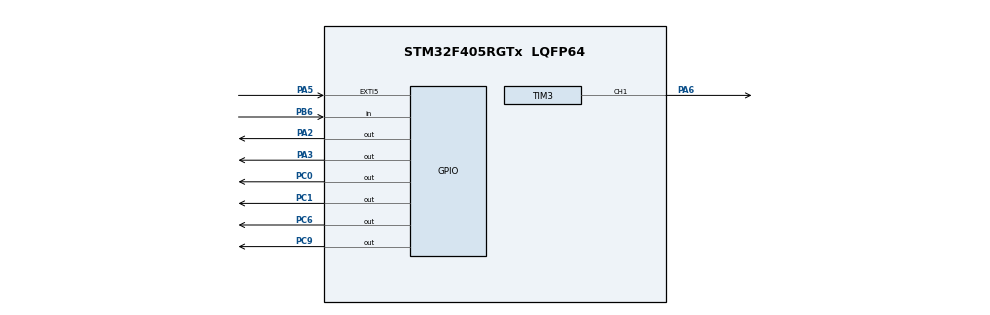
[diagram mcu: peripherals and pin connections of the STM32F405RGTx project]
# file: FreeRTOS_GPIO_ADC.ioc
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Mcu.Family=STM32F4
Mcu.Name=STM32F405RGTx
Mcu.Package=LQFP64
NVIC.PriorityGroup=NVIC_PRIORITYGROUP_4
NVIC.TIM6_DAC_IRQn=true\:15\:0\:false\:false\:true\:false\:true\:true
NVIC.TimeBase=TIM6_DAC_IRQn
NVIC.TimeBaseIP=TIM6
PA2.Signal=GPIO_Output
PA3.Signal=GPIO_Output
PA5.Signal=GPXTI5
PA6.Signal=S_TIM3_CH1
PB6.Signal=GPIO_Input
PC0.Signal=GPIO_Output
PC1.Signal=GPIO_Output
PC6.Signal=GPIO_Output
PC9.Signal=GPIO_Output
ProjectManager.HeapSize=0x200
ProjectManager.StackSize=0x400
ProjectManager.TargetToolchain=STM32CubeIDE
RCC.AHBFreq_Value=16000000
RCC.APB1Freq_Value=16000000
RCC.APB2Freq_Value=16000000
RCC.CortexFreq_Value=16000000
RCC.HSE_VALUE=25000000
RCC.HSI_VALUE=16000000
RCC.LSE_VALUE=32768
RCC.SYSCLKFreq_VALUE=16000000
RCC.VCOOutputFreq_Value=192000000
SH.S_TIM3_CH1.0=TIM3_CH1,PWM Generation1 CH1
TIM2.Period=65535
TIM2.Prescaler=15
TIM3.Channel-PWM\ Generation1\ CH1=TIM_CHANNEL_1
TIM3.OCFastMode_PWM-PWM\ Generation1\ CH1=TIM_OCFAST_ENABLE
TIM3.Period=799
TIM3.Prescaler=1
VP_SYS_VS_tim6.Mode=TIM6
VP_TIM2_VS_ClockSourceINT.Mode=Internal
VP_TIM3_VS_ClockSourceINT.Mode=Internal
board=custom

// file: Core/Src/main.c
/* USER CODE BEGIN Header */
/**
 ******************************************************************************
 * @file           : main.c
 * @brief          : Main program body
 ******************************************************************************
 * @attention
 *
 * Copyright (c) 2025 STMicroelectronics.
 * All rights reserved.
 *
 * This software is licensed under terms that can be found in the LICENSE file
 * in the root directory of this software component.
 * If no LICENSE file comes with this software, it is provided AS-IS.
 *
 ******************************************************************************
 */
/* USER CODE END Header */
#include "main.h"

/* USER CODE BEGIN Includes */
#include "stdio.h"
#include "dht11.h"
#include "stdint.h"
#include "string.h"
#include "math.h"
#include "lcd.h"
#include "FreeRTOS.h"
#include "task.h"
/* USER CODE END Includes */

TIM_HandleTypeDef htim2;
TIM_HandleTypeDef htim3;

/* USER CODE BEGIN PV */
TaskHandle_t x1Handle;
TaskHandle_t x2Handle;
BaseType_t x1Return;
BaseType_t x2Return;
uint8_t DHT11_Read(DHT11_Data *data);
DHT11_Data dht;
uint8_t pir_status = 0;
volatile uint8_t vibrationDetected = 0;
volatile uint32_t runtimeStatsTimer = 0;
uint8_t flag = 0;
char buffer[512];

/* USER CODE END PV */

void SystemClock_Config(void);
static void MX_GPIO_Init(void);
static void MX_TIM2_Init(void);
static void MX_TIM3_Init(void);
/* USER CODE BEGIN PFP */
void speed_monitoring(void *pvParameters);
void safety_monitoring(void *pvParameters);
void motor_config(void);
/* USER CODE END PFP */

/* USER CODE BEGIN 0 */
void ConfigureRunTimeStatsTimer(void) {
	__HAL_RCC_TIM2_CLK_ENABLE();

	htim2.Instance = TIM2;
	htim2.Init.Prescaler = (SystemCoreClock / 1000000) - 1;  // 1 MHz
	htim2.Init.CounterMode = TIM_COUNTERMODE_UP;
	htim2.Init.Period = 0xFFFFFFFF;
	htim2.Init.ClockDivision = TIM_CLOCKDIVISION_DIV1;
	HAL_TIM_Base_Init(&htim2);
	HAL_TIM_Base_Start(&htim2);
	runtimeStatsTimer = __HAL_TIM_GET_COUNTER(&htim2);
}
/* USER CODE END 0 */

int main(void) {

	/* MCU Configuration--------------------------------------------------------*/

	/* Reset of all peripherals, Initializes the Flash interface and the Systick. */
	HAL_Init();

	/* Configure the system clock */
	SystemClock_Config();

	/* Initialize all configured peripherals */
	MX_GPIO_Init();
	MX_TIM2_Init();
	MX_TIM3_Init();
	/* USER CODE BEGIN 2 */
	//DHT11_Init();
	DWT_Init();
	HAL_TIM_Base_Start(&htim2);
	ConfigureRunTimeStatsTimer();
	LcdInit();
	motor_config();

	HAL_NVIC_SetPriority(EXTI9_5_IRQn, 0, 0);
	HAL_NVIC_EnableIRQ(EXTI9_5_IRQn);

	x1Return = xTaskCreate(speed_monitoring, "MOTOR CONTROL",
	configMINIMAL_STACK_SIZE * 3,
	NULL, 2, &x1Handle);

	x2Return = xTaskCreate(safety_monitoring, "HUMAN CONTROL",
	configMINIMAL_STACK_SIZE * 3,
	NULL, 1, &x2Handle);
	vTaskStartScheduler();
	/* USER CODE END 2 */

	/* Infinite loop */
	/* USER CODE BEGIN WHILE */
	while (1) {

//		speed_monitoring();
//		safety_monitoring();
//		HAL_Delay(1000);

		/* USER CODE END WHILE */

	}
}

void SystemClock_Config(void) {
	RCC_OscInitTypeDef RCC_OscInitStruct = { 0 };
	RCC_ClkInitTypeDef RCC_ClkInitStruct = { 0 };

	/** Configure the main internal regulator output voltage
	 */
	__HAL_RCC_PWR_CLK_ENABLE();
	__HAL_PWR_VOLTAGESCALING_CONFIG(PWR_REGULATOR_VOLTAGE_SCALE1);

	/** Initializes the RCC Oscillators according to the specified parameters
	 * in the RCC_OscInitTypeDef structure.
	 */
	RCC_OscInitStruct.OscillatorType = RCC_OSCILLATORTYPE_HSI;
	RCC_OscInitStruct.HSIState = RCC_HSI_ON;
	RCC_OscInitStruct.HSICalibrationValue = RCC_HSICALIBRATION_DEFAULT;
	RCC_OscInitStruct.PLL.PLLState = RCC_PLL_ON;
	RCC_OscInitStruct.PLL.PLLSource = RCC_PLLSOURCE_HSI;
	RCC_OscInitStruct.PLL.PLLM = 8;
	RCC_OscInitStruct.PLL.PLLN = 84;
	RCC_OscInitStruct.PLL.PLLP = RCC_PLLP_DIV2;
	RCC_OscInitStruct.PLL.PLLQ = 4;
	if (HAL_RCC_OscConfig(&RCC_OscInitStruct) != HAL_OK) {
		Error_Handler();
	}

	/** Initializes the CPU, AHB and APB buses clocks
	 */
	RCC_ClkInitStruct.ClockType = RCC_CLOCKTYPE_HCLK | RCC_CLOCKTYPE_SYSCLK
			| RCC_CLOCKTYPE_PCLK1 | RCC_CLOCKTYPE_PCLK2;
	RCC_ClkInitStruct.SYSCLKSource = RCC_SYSCLKSOURCE_PLLCLK;
	RCC_ClkInitStruct.AHBCLKDivider = RCC_SYSCLK_DIV1;
	RCC_ClkInitStruct.APB1CLKDivider = RCC_HCLK_DIV2;
	RCC_ClkInitStruct.APB2CLKDivider = RCC_HCLK_DIV1;

	if (HAL_RCC_ClockConfig(&RCC_ClkInitStruct, FLASH_LATENCY_2) != HAL_OK) {
		Error_Handler();
	}
}

static void MX_TIM2_Init(void) {

	TIM_ClockConfigTypeDef sClockSourceConfig = { 0 };
	TIM_MasterConfigTypeDef sMasterConfig = { 0 };

	htim2.Instance = TIM2;
	htim2.Init.Prescaler = 15;
	htim2.Init.CounterMode = TIM_COUNTERMODE_UP;
	htim2.Init.Period = 65535;
	htim2.Init.ClockDivision = TIM_CLOCKDIVISION_DIV1;
	htim2.Init.AutoReloadPreload = TIM_AUTORELOAD_PRELOAD_DISABLE;
	if (HAL_TIM_Base_Init(&htim2) != HAL_OK) {
		Error_Handler();
	}
	sClockSourceConfig.ClockSource = TIM_CLOCKSOURCE_INTERNAL;
	if (HAL_TIM_ConfigClockSource(&htim2, &sClockSourceConfig) != HAL_OK) {
		Error_Handler();
	}
	sMasterConfig.MasterOutputTrigger = TIM_TRGO_RESET;
	sMasterConfig.MasterSlaveMode = TIM_MASTERSLAVEMODE_DISABLE;
	if (HAL_TIMEx_MasterConfigSynchronization(&htim2, &sMasterConfig)
			!= HAL_OK) {
		Error_Handler();
	}

}

static void MX_TIM3_Init(void) {

	TIM_ClockConfigTypeDef sClockSourceConfig = { 0 };
	TIM_MasterConfigTypeDef sMasterConfig = { 0 };
	TIM_OC_InitTypeDef sConfigOC = { 0 };

	htim3.Instance = TIM3;
	htim3.Init.Prescaler = 1;
	htim3.Init.CounterMode = TIM_COUNTERMODE_UP;
	htim3.Init.Period = 799;
	htim3.Init.ClockDivision = TIM_CLOCKDIVISION_DIV1;
	htim3.Init.AutoReloadPreload = TIM_AUTORELOAD_PRELOAD_DISABLE;
	if (HAL_TIM_Base_Init(&htim3) != HAL_OK) {
		Error_Handler();
	}
	sClockSourceConfig.ClockSource = TIM_CLOCKSOURCE_INTERNAL;
	if (HAL_TIM_ConfigClockSource(&htim3, &sClockSourceConfig) != HAL_OK) {
		Error_Handler();
	}
	if (HAL_TIM_PWM_Init(&htim3) != HAL_OK) {
		Error_Handler();
	}
	sMasterConfig.MasterOutputTrigger = TIM_TRGO_RESET;
	sMasterConfig.MasterSlaveMode = TIM_MASTERSLAVEMODE_DISABLE;
	if (HAL_TIMEx_MasterConfigSynchronization(&htim3, &sMasterConfig)
			!= HAL_OK) {
		Error_Handler();
	}
	sConfigOC.OCMode = TIM_OCMODE_PWM1;
	sConfigOC.Pulse = 0;
	sConfigOC.OCPolarity = TIM_OCPOLARITY_HIGH;
	sConfigOC.OCFastMode = TIM_OCFAST_ENABLE;
	if (HAL_TIM_PWM_ConfigChannel(&htim3, &sConfigOC, TIM_CHANNEL_1)
			!= HAL_OK) {
		Error_Handler();
	}
	HAL_TIM_MspPostInit(&htim3);

}

static void MX_GPIO_Init(void) {
	GPIO_InitTypeDef GPIO_InitStruct = { 0 };

	/* GPIO Ports Clock Enable */
	__HAL_RCC_GPIOC_CLK_ENABLE();
	__HAL_RCC_GPIOA_CLK_ENABLE();
	__HAL_RCC_GPIOB_CLK_ENABLE();

	/*Configure GPIO pin Output Level */
	HAL_GPIO_WritePin(GPIOC, GPIO_PIN_0 | GPIO_PIN_1 | GPIO_PIN_6 | GPIO_PIN_9,
			GPIO_PIN_RESET);

	/*Configure GPIO pin Output Level */
	HAL_GPIO_WritePin(GPIOA, GPIO_PIN_2 | GPIO_PIN_3, GPIO_PIN_RESET);

	/*Configure GPIO pins : PC0 PC1 PC6 PC9 */
	GPIO_InitStruct.Pin = GPIO_PIN_0 | GPIO_PIN_1 | GPIO_PIN_6 | GPIO_PIN_9;
	GPIO_InitStruct.Mode = GPIO_MODE_OUTPUT_PP;
	GPIO_InitStruct.Pull = GPIO_NOPULL;
	GPIO_InitStruct.Speed = GPIO_SPEED_FREQ_LOW;
	HAL_GPIO_Init(GPIOC, &GPIO_InitStruct);

	/*Configure GPIO pins : PA2 PA3 */
	GPIO_InitStruct.Pin = GPIO_PIN_2 | GPIO_PIN_3;
	GPIO_InitStruct.Mode = GPIO_MODE_OUTPUT_PP;
	GPIO_InitStruct.Pull = GPIO_NOPULL;
	GPIO_InitStruct.Speed = GPIO_SPEED_FREQ_LOW;
	HAL_GPIO_Init(GPIOA, &GPIO_InitStruct);

	/*Configure GPIO pin : PA5 */
	GPIO_InitStruct.Pin = GPIO_PIN_5;
	GPIO_InitStruct.Mode = GPIO_MODE_IT_RISING;
	GPIO_InitStruct.Pull = GPIO_NOPULL;
	HAL_GPIO_Init(GPIOA, &GPIO_InitStruct);

	/*Configure GPIO pin : PB6 */
	GPIO_InitStruct.Pin = GPIO_PIN_6;
	GPIO_InitStruct.Mode = GPIO_MODE_INPUT;
	GPIO_InitStruct.Pull = GPIO_NOPULL;
	HAL_GPIO_Init(GPIOB, &GPIO_InitStruct);

}

/* USER CODE BEGIN 4 */

void motor_config(void) {
	HAL_GPIO_WritePin(GPIOA, GPIO_PIN_3, GPIO_PIN_SET); //STBY
	HAL_GPIO_WritePin(GPIOC, GPIO_PIN_0, GPIO_PIN_SET); //AIN1
	HAL_GPIO_WritePin(GPIOC, GPIO_PIN_1, GPIO_PIN_RESET); //AIN2

	HAL_TIM_PWM_Start(&htim3, TIM_CHANNEL_1);

	__HAL_TIM_SET_COMPARE(&htim3, TIM_CHANNEL_1, 300);
}

void speed_monitoring(void *pvParameters) {
	while (1) {
		if (DHT11_GetData(GPIOA, GPIO_PIN_2, &dht)) {
			LcdFxn(0, 0x01);
			// Use dht.Temperature and dht.Humidity
			lprint(0x80, "Tem:");
			aprint(0x86, dht.Temperature);
			lprint(0xC0, "hum:");
			aprint(0xC6, dht.Humidity);

			vTaskDelay(pdMS_TO_TICKS(1500));
			if (dht.Temperature >= 27 && dht.Humidity >= 73 && flag != 1) {
				LcdFxn(0, 0x01);
				lprint(0x80, "Temperature exceeded");
				// Gradual motor slowdown using PWM
				uint16_t pwm_values[] = { 600, 400, 200, 0 };
				for (int i = 0; i < 4; i++) {
					__HAL_TIM_SET_COMPARE(&htim3, TIM_CHANNEL_1, pwm_values[i]);
					HAL_Delay(2000);
				}
				flag = 1;
			}

			if (vibrationDetected) {
				LcdFxn(0, 0x01);
				lprint(0x80, "High Vibration Detected");

				if (flag != 1) {
					// Gradual motor slowdown using PWM
					uint16_t pwm_values[] = { 600, 400, 200, 0 };
					for (int i = 0; i < 4; i++) {
						__HAL_TIM_SET_COMPARE(&htim3, TIM_CHANNEL_1,
								pwm_values[i]);
						HAL_Delay(2000);
					}
					flag = 1;
				}

				vibrationDetected = 0;
			}

			else if (dht.Temperature <= 26 && dht.Humidity >= 65 && flag == 1
					&& vibrationDetected == 0) {
				flag = 0;
				__HAL_TIM_SET_COMPARE(&htim3, TIM_CHANNEL_1, 300);
				//HAL_Delay(2000);

			}
		}
		vTaskGetRunTimeStats(buffer);
		printf("%s\n", buffer);
		vTaskDelay(pdMS_TO_TICKS(2000));
	}
}

void safety_monitoring(void *pvParameters) {
	while (1) {
		pir_status = HAL_GPIO_ReadPin(GPIOB, GPIO_PIN_6);

		if (pir_status) {
			// Motion detected
			LcdFxn(0, 0x01);  // Clear LCD
			lprint(0x80, "Motion Detected");
			HAL_GPIO_WritePin(GPIOC, GPIO_PIN_6, GPIO_PIN_RESET); // LED ON
			//HAL_GPIO_WritePin(GPIOC, GPIO_PIN_9, GPIO_PIN_SET);// BUZZER ON
			lprint(0xC8, "PIR:1");

		} else {
			LcdFxn(0, 0x01);
			lprint(0xC8, "PIR:0");
			HAL_GPIO_WritePin(GPIOC, GPIO_PIN_6, GPIO_PIN_SET);   // LED OFF
			//HAL_GPIO_WritePin(GPIOC, GPIO_PIN_9, GPIO_PIN_RESET); // BUZZER OFF
		}
		vTaskGetRunTimeStats(buffer);
		printf("%s\n", buffer);
		vTaskDelay(pdMS_TO_TICKS(2000));
	}
}

void EXTI0_IRQHandler(void) {
	HAL_GPIO_EXTI_IRQHandler(GPIO_PIN_0);
}

void EXTI9_5_IRQHandler(void) {
	HAL_GPIO_EXTI_IRQHandler(GPIO_PIN_5);
}

void HAL_GPIO_EXTI_Callback(uint16_t GPIO_Pin) {
	if (GPIO_Pin == GPIO_PIN_5) {  // PA5
		vibrationDetected = 1;
	}
}

/* USER CODE END 4 */

void HAL_TIM_PeriodElapsedCallback(TIM_HandleTypeDef *htim) {
	if (htim->Instance == TIM6) {
		HAL_IncTick();
	}
}

void Error_Handler(void) {
	__disable_irq();
	while (1) {
	}
}
